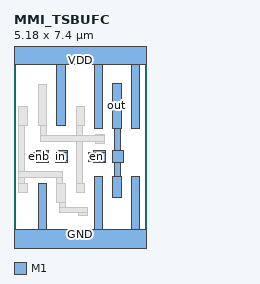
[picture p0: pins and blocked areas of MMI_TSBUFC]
MACRO MMI_TSBUFC
	CLASS CORE ;
	FOREIGN MMI_TSBUFC 0 0 ;
	SIZE 5.18 BY 7.4 ;
	SYMMETRY X Y ;
	SITE CORE1 ;
	PIN out
		DIRECTION output ;
		USE SIGNAL ;
		PORT
			LAYER M1 ;
			RECT 3.84 4.43 4.18 6.19 ;
			LAYER M1 ;
			RECT 3.93 3.555 4.16 4.43 ;
			LAYER M1 ;
			RECT 3.845 3.105 4.25 3.555 ;
			LAYER M1 ;
			RECT 3.93 2.555 4.16 3.105 ;
			LAYER M1 ;
			RECT 3.84 1.715 4.18 2.555 ;
		END
		AntennaDiffArea 1.4904 ;
	END out
	PIN GND
		DIRECTION inout ;
		USE GROUND ;
		PORT
			LAYER M1 ;
			RECT 0.94 0.5 1.28 2.285 ;
			LAYER M1 ;
			RECT 3.12 0.5 3.46 2.555 ;
			LAYER M1 ;
			RECT 4.56 0.5 4.9 2.555 ;
			LAYER M1 ;
			RECT 0 -0.5 5.18 0.5 ;
		END
	END GND
	PIN enb
		DIRECTION input ;
		USE SIGNAL ;
		PORT
			LAYER M1 ;
			RECT 0.885 3.5 1.335 3.555 ;
			LAYER M1 ;
			RECT 0.64 3.16 1.335 3.5 ;
			LAYER M1 ;
			RECT 0.885 3.105 1.335 3.16 ;
		END
		AntennaGateArea 0.2268 ;
	END enb
	PIN VDD
		DIRECTION inout ;
		USE POWER ;
		PORT
			LAYER M1 ;
			RECT 0 6.9 5.18 7.9 ;
			LAYER M1 ;
			RECT 1.66 4.53 2 6.9 ;
			LAYER M1 ;
			RECT 3.12 4.43 3.46 6.9 ;
			LAYER M1 ;
			RECT 4.56 4.43 4.9 6.9 ;
		END
	END VDD
	PIN en
		DIRECTION input ;
		USE SIGNAL ;
		PORT
			LAYER M1 ;
			RECT 3.105 3.49 3.555 3.555 ;
			LAYER M1 ;
			RECT 2.89 3.15 3.555 3.49 ;
			LAYER M1 ;
			RECT 3.105 3.105 3.555 3.15 ;
		END
		AntennaGateArea 0.2268 ;
	END en
	PIN in
		DIRECTION input ;
		USE SIGNAL ;
		PORT
			LAYER M1 ;
			RECT 1.625 3.5 2.075 3.555 ;
			LAYER M1 ;
			RECT 1.565 3.16 2.075 3.5 ;
			LAYER M1 ;
			RECT 1.625 3.105 2.075 3.16 ;
		END
		AntennaGateArea 0.4536 ;
	END in
	OBS
		LAYER M1 ;
		RECT 0.18 4.53 0.52 5.29 ;
		LAYER M1 ;
		RECT 0.94 4.53 1.28 6.13 ;
		LAYER M1 ;
		RECT 2.42 4.53 2.76 5.29 ;
		LAYER M1 ;
		RECT 0.18 2.755 0.41 4.53 ;
		LAYER M1 ;
		RECT 1.05 4.135 1.28 4.53 ;
		LAYER M1 ;
		RECT 2.42 4.135 2.65 4.53 ;
		LAYER M1 ;
		RECT 3.185 4.135 3.525 4.19 ;
		LAYER M1 ;
		RECT 1.05 3.905 3.525 4.135 ;
		LAYER M1 ;
		RECT 1.66 2.755 1.89 2.76 ;
		LAYER M1 ;
		RECT 0.18 2.525 1.89 2.755 ;
		LAYER M1 ;
		RECT 0.18 2.285 0.41 2.525 ;
		LAYER M1 ;
		RECT 1.66 2.285 1.89 2.525 ;
		LAYER M1 ;
		RECT 2.42 2.285 2.65 3.905 ;
		LAYER M1 ;
		RECT 3.185 3.85 3.525 3.905 ;
		LAYER M1 ;
		RECT 0.18 1.945 0.52 2.285 ;
		LAYER M1 ;
		RECT 1.66 1.525 2 2.285 ;
		LAYER M1 ;
		RECT 2.42 1.945 2.76 2.285 ;
		LAYER M1 ;
		RECT 1.77 1.36 2 1.525 ;
		LAYER M1 ;
		RECT 1.77 1.13 2.85 1.36 ;
		LAYER M1 ;
		RECT 2.51 1.02 2.85 1.13 ;
	END
END MMI_TSBUFC
